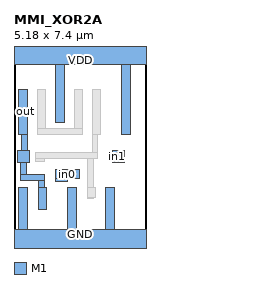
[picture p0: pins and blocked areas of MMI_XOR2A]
MACRO MMI_XOR2A
	CLASS CORE ;
	FOREIGN MMI_XOR2A 0 0 ;
	SIZE 5.18 BY 7.4 ;
	SYMMETRY X Y ;
	SITE CORE1 ;
	PIN out
		DIRECTION output ;
		USE SIGNAL ;
		PORT
			LAYER M1 ;
			RECT 0.18 4.185 0.52 5.945 ;
			LAYER M1 ;
			RECT 0.29 3.555 0.52 4.185 ;
			LAYER M1 ;
			RECT 0.145 3.105 0.595 3.555 ;
			LAYER M1 ;
			RECT 0.26 2.615 0.49 3.105 ;
			LAYER M1 ;
			RECT 0.26 2.385 1.17 2.615 ;
			LAYER M1 ;
			RECT 0.94 2.125 1.17 2.385 ;
			LAYER M1 ;
			RECT 0.94 1.285 1.28 2.125 ;
		END
		AntennaDiffArea 1.3708 ;
	END out
	PIN in1
		DIRECTION input ;
		USE SIGNAL ;
		PORT
			LAYER M1 ;
			RECT 3.845 3.5 4.295 3.555 ;
			LAYER M1 ;
			RECT 3.71 3.16 4.295 3.5 ;
			LAYER M1 ;
			RECT 3.845 3.105 4.295 3.16 ;
		END
		AntennaGateArea 0.9108 ;
	END in1
	PIN GND
		DIRECTION inout ;
		USE GROUND ;
		PORT
			LAYER M1 ;
			RECT 0.18 0.5 0.52 2.125 ;
			LAYER M1 ;
			RECT 2.09 0.5 2.43 2.125 ;
			LAYER M1 ;
			RECT 3.57 0.5 3.91 2.125 ;
			LAYER M1 ;
			RECT 0 -0.5 5.18 0.5 ;
		END
	END GND
	PIN VDD
		DIRECTION inout ;
		USE POWER ;
		PORT
			LAYER M1 ;
			RECT 0 6.9 5.18 7.9 ;
			LAYER M1 ;
			RECT 1.62 4.665 1.96 6.9 ;
			LAYER M1 ;
			RECT 4.19 4.185 4.53 6.9 ;
		END
	END VDD
	PIN in0
		DIRECTION input ;
		USE SIGNAL ;
		PORT
			LAYER M1 ;
			RECT 2.2 2.81 2.54 2.82 ;
			LAYER M1 ;
			RECT 1.625 2.48 2.54 2.81 ;
			LAYER M1 ;
			RECT 1.625 2.47 2.38 2.48 ;
			LAYER M1 ;
			RECT 1.625 2.365 2.075 2.47 ;
		END
		AntennaGateArea 0.9108 ;
	END in0
	OBS
		LAYER M1 ;
		RECT 0.9 4.415 1.24 5.945 ;
		LAYER M1 ;
		RECT 2.34 4.415 2.68 5.945 ;
		LAYER M1 ;
		RECT 0.9 4.185 2.68 4.415 ;
		LAYER M1 ;
		RECT 3.04 4.185 3.38 5.945 ;
		LAYER M1 ;
		RECT 0.84 3.48 1.18 3.49 ;
		LAYER M1 ;
		RECT 3.04 3.48 3.27 4.185 ;
		LAYER M1 ;
		RECT 0.84 3.25 3.27 3.48 ;
		LAYER M1 ;
		RECT 0.84 3.15 1.18 3.25 ;
		LAYER M1 ;
		RECT 2.85 2.125 3.08 3.25 ;
		LAYER M1 ;
		RECT 2.85 1.745 3.19 2.125 ;
		LAYER M1 ;
		RECT 2.85 1.71 3.08 1.745 ;
	END
END MMI_XOR2A
